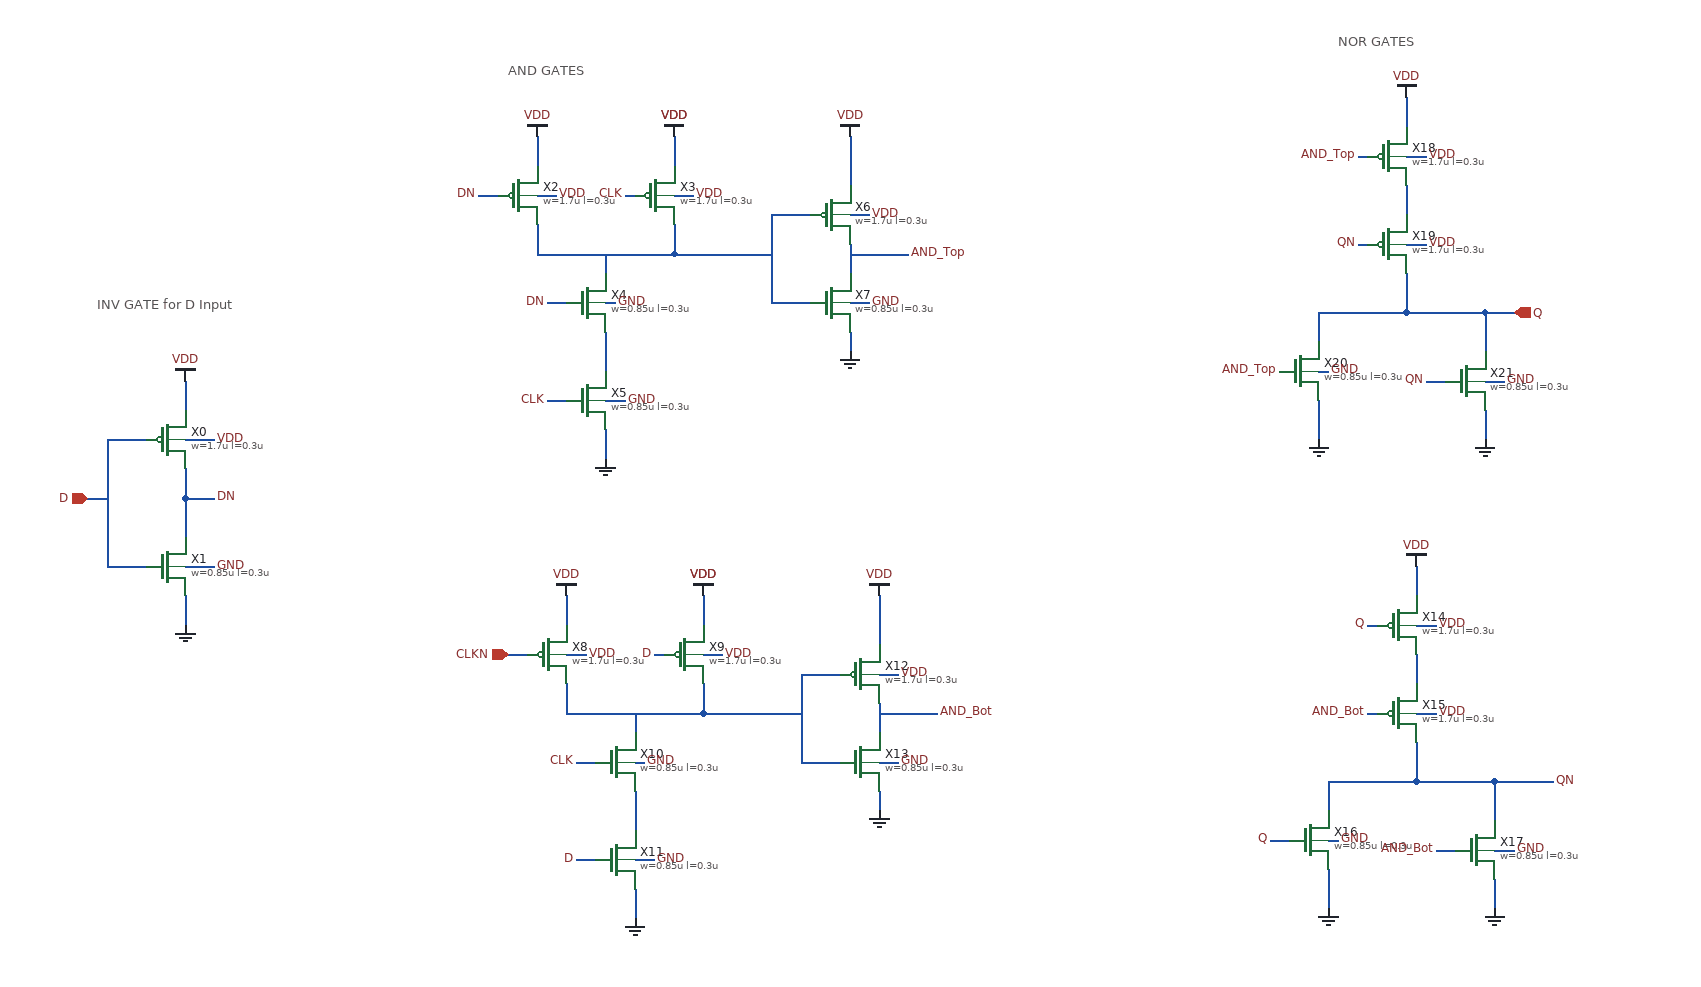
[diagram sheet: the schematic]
v {xschem version=3.0.0 file_version=1.2 }
G {}
K {}
V {}
S {}
E {}
T {AND GATES} 520 -910 0 0 0.4 0.4 {}
T {NOR GATES} 1370 -940 0 0 0.4 0.4 {}
T {INV GATE for D Input} 100 -670 0 0 0.4 0.4 {}
N 190 -580 190 -550 { lab=VDD}
N 190 -490 190 -460 { lab=DN}
N 190 -460 190 -420 { lab=DN}
N 190 -360 190 -330 { lab=GND}
N 130 -520 150 -520 { lab=D}
N 110 -520 110 -390 { lab=D}
N 90 -460 110 -460 { lab=D}
N 110 -520 130 -520 { lab=D}
N 110 -390 150 -390 { lab=D}
N 190 -520 220 -520 { lab=VDD}
N 190 -390 220 -390 { lab=GND}
N 190 -460 220 -460 { lab=DN}
N 550 -830 550 -800 { lab=VDD}
N 690 -830 690 -800 { lab=VDD}
N 550 -740 550 -710 { lab=#net1}
N 550 -710 690 -710 { lab=#net1}
N 690 -740 690 -710 { lab=#net1}
N 620 -710 620 -690 { lab=#net1}
N 620 -630 620 -590 { lab=#net2}
N 620 -530 620 -500 { lab=GND}
N 490 -770 510 -770 { lab=DN}
N 640 -770 650 -770 { lab=CLK}
N 870 -710 930 -710 { lab=AND_Top}
N 550 -770 570 -770 { lab=VDD}
N 690 -770 710 -770 { lab=VDD}
N 620 -660 630 -660 { lab=GND}
N 620 -560 640 -560 { lab=GND}
N 560 -660 580 -660 { lab=DN}
N 560 -560 580 -560 { lab=CLK}
N 870 -720 870 -690 { lab=AND_Top}
N 790 -660 830 -660 { lab=#net1}
N 790 -740 790 -660 { lab=#net1}
N 790 -750 790 -740 { lab=#net1}
N 790 -750 830 -750 { lab=#net1}
N 690 -710 790 -710 { lab=#net1}
N 870 -830 870 -780 { lab=VDD}
N 870 -630 870 -610 { lab=GND}
N 870 -750 890 -750 { lab=VDD}
N 870 -660 890 -660 { lab=GND}
N 580 -360 580 -330 { lab=VDD}
N 720 -360 720 -330 { lab=VDD}
N 580 -270 580 -240 { lab=#net3}
N 580 -240 720 -240 { lab=#net3}
N 720 -270 720 -240 { lab=#net3}
N 650 -240 650 -220 { lab=#net3}
N 650 -160 650 -120 { lab=#net4}
N 650 -60 650 -30 { lab=GND}
N 520 -300 540 -300 { lab=CLK}
N 670 -300 680 -300 { lab=D}
N 900 -240 960 -240 { lab=AND_Bot}
N 580 -300 600 -300 { lab=VDD}
N 720 -300 740 -300 { lab=VDD}
N 650 -190 660 -190 { lab=GND}
N 650 -90 670 -90 { lab=GND}
N 590 -190 610 -190 { lab=CLK}
N 590 -90 610 -90 { lab=D}
N 900 -250 900 -220 { lab=AND_Bot}
N 820 -190 860 -190 { lab=#net3}
N 820 -270 820 -190 { lab=#net3}
N 820 -280 820 -270 { lab=#net3}
N 820 -280 860 -280 { lab=#net3}
N 720 -240 820 -240 { lab=#net3}
N 900 -360 900 -310 { lab=VDD}
N 900 -160 900 -140 { lab=GND}
N 900 -280 920 -280 { lab=VDD}
N 900 -190 920 -190 { lab=GND}
N 1450 -390 1450 -360 { lab=VDD}
N 1450 -300 1450 -270 { lab=#net5}
N 1360 -80 1360 -40 { lab=GND}
N 1530 -70 1530 -40 { lab=GND}
N 1400 -240 1410 -240 { lab=AND_Bot}
N 1450 -330 1470 -330 { lab=VDD}
N 1450 -240 1470 -240 { lab=VDD}
N 1360 -110 1370 -110 { lab=GND}
N 1530 -100 1550 -100 { lab=GND}
N 1300 -110 1320 -110 { lab=Q}
N 1470 -100 1490 -100 { lab=AND_Bot}
N 1360 -170 1360 -140 { lab=QN}
N 1450 -210 1450 -170 { lab=QN}
N 1360 -170 1450 -170 { lab=QN}
N 1530 -170 1530 -130 { lab=QN}
N 1450 -170 1530 -170 { lab=QN}
N 1400 -330 1410 -330 { lab=Q}
N 1440 -870 1440 -840 { lab=VDD}
N 1440 -780 1440 -750 { lab=#net6}
N 1350 -560 1350 -520 { lab=GND}
N 1520 -550 1520 -520 { lab=GND}
N 1390 -720 1400 -720 { lab=QN}
N 1440 -810 1460 -810 { lab=VDD}
N 1440 -720 1460 -720 { lab=VDD}
N 1350 -590 1360 -590 { lab=GND}
N 1520 -580 1540 -580 { lab=GND}
N 1460 -580 1480 -580 { lab=QN}
N 1350 -650 1350 -620 { lab=Q}
N 1440 -690 1440 -650 { lab=Q}
N 1350 -650 1440 -650 { lab=Q}
N 1520 -650 1520 -610 { lab=Q}
N 1440 -650 1520 -650 { lab=Q}
N 1520 -650 1550 -650 { lab=Q}
N 1390 -810 1400 -810 { lab=AND_Top}
N 1530 -170 1590 -170 { lab=QN}
C {vdd.sym} 190 -580 0 0 {name=l1 lab=VDD}
C {gnd.sym} 190 -330 0 0 {name=l3 lab=GND}
C {ipin.sym} 90 -460 0 0 {name=p3 lab=D
}
C {pmos4.sym} 170 -520 0 0 {name=X0 model=pmos_3p3 w=1.7u l=0.3u m=1}
C {nmos4.sym} 170 -390 0 0 {name=X1 model=nmos_3p3 w=0.85u l=0.3u m=1}
C {lab_wire.sym} 220 -520 2 0 {name=l2 sig_type=std_logic lab=VDD
}
C {lab_wire.sym} 220 -390 2 0 {name=l4 sig_type=std_logic lab=GND
}
C {lab_wire.sym} 220 -460 2 0 {name=l5 sig_type=std_logic lab=DN}
C {vdd.sym} 550 -830 0 0 {name=l6 lab=VDD}
C {vdd.sym} 690 -830 0 0 {name=l7 lab=VDD}
C {gnd.sym} 620 -500 0 0 {name=l8 lab=GND}
C {pmos4.sym} 530 -770 0 0 {name=X2 model=pmos_3p3 w=1.7u l=0.3u m=1}
C {pmos4.sym} 670 -770 0 0 {name=X3 model=pmos_3p3 w=1.7u l=0.3u m=1}
C {nmos4.sym} 600 -660 0 0 {name=X4 model=nmos_3p3 w=0.85u l=0.3u m=1}
C {nmos4.sym} 600 -560 0 0 {name=X5 model=nmos_3p3 w=0.85u l=0.3u m=1}
C {lab_wire.sym} 570 -770 2 0 {name=l9 sig_type=std_logic lab=VDD}
C {lab_wire.sym} 710 -770 2 0 {name=l10 sig_type=std_logic lab=VDD}
C {lab_wire.sym} 630 -660 2 0 {name=l11 sig_type=std_logic lab=GND}
C {lab_wire.sym} 640 -560 2 0 {name=l12 sig_type=std_logic lab=GND}
C {lab_wire.sym} 560 -560 0 0 {name=l14 sig_type=std_logic lab=CLK}
C {pmos4.sym} 850 -750 0 0 {name=X6 model=pmos_3p3 w=1.7u l=0.3u m=1}
C {nmos4.sym} 850 -660 0 0 {name=X7 model=nmos_3p3 w=0.85u l=0.3u m=1}
C {vdd.sym} 690 -830 0 0 {name=l15 lab=VDD}
C {vdd.sym} 870 -830 0 0 {name=l16 lab=VDD}
C {gnd.sym} 870 -610 0 0 {name=l17 lab=GND}
C {lab_wire.sym} 890 -750 2 0 {name=l18 sig_type=std_logic lab=VDD}
C {lab_wire.sym} 890 -660 2 0 {name=l19 sig_type=std_logic lab=GND}
C {vdd.sym} 580 -360 0 0 {name=l20 lab=VDD}
C {vdd.sym} 720 -360 0 0 {name=l21 lab=VDD}
C {gnd.sym} 650 -30 0 0 {name=l22 lab=GND}
C {ipin.sym} 520 -300 0 0 {name=p2 lab=CLKN
}
C {pmos4.sym} 560 -300 0 0 {name=X8 model=pmos_3p3 w=1.7u l=0.3u m=1}
C {pmos4.sym} 700 -300 0 0 {name=X9 model=pmos_3p3 w=1.7u l=0.3u m=1}
C {nmos4.sym} 630 -190 0 0 {name=X10 model=nmos_3p3 w=0.85u l=0.3u m=1}
C {nmos4.sym} 630 -90 0 0 {name=X11 model=nmos_3p3 w=0.85u l=0.3u m=1}
C {lab_wire.sym} 600 -300 2 0 {name=l23 sig_type=std_logic lab=VDD}
C {lab_wire.sym} 740 -300 2 0 {name=l24 sig_type=std_logic lab=VDD}
C {lab_wire.sym} 660 -190 2 0 {name=l25 sig_type=std_logic lab=GND}
C {lab_wire.sym} 670 -90 2 0 {name=l26 sig_type=std_logic lab=GND}
C {lab_wire.sym} 590 -190 0 0 {name=l27 sig_type=std_logic lab=CLK}
C {lab_wire.sym} 590 -90 0 0 {name=l28 sig_type=std_logic lab=D}
C {pmos4.sym} 880 -280 0 0 {name=X12 model=pmos_3p3 w=1.7u l=0.3u m=1}
C {nmos4.sym} 880 -190 0 0 {name=X13 model=nmos_3p3 w=0.85u l=0.3u m=1}
C {vdd.sym} 720 -360 0 0 {name=l29 lab=VDD}
C {vdd.sym} 900 -360 0 0 {name=l30 lab=VDD}
C {gnd.sym} 900 -140 0 0 {name=l31 lab=GND}
C {lab_wire.sym} 920 -280 2 0 {name=l32 sig_type=std_logic lab=VDD}
C {lab_wire.sym} 920 -190 2 0 {name=l33 sig_type=std_logic lab=GND}
C {vdd.sym} 1450 -390 0 0 {name=l34 lab=VDD}
C {gnd.sym} 1360 -40 0 0 {name=l35 lab=GND}
C {pmos4.sym} 1430 -330 0 0 {name=X14 model=pmos_3p3 w=1.7u l=0.3u m=1}
C {pmos4.sym} 1430 -240 0 0 {name=X15 model=pmos_3p3 w=1.7u l=0.3u m=1}
C {nmos4.sym} 1340 -110 0 0 {name=X16 model=nmos_3p3 w=0.85u l=0.3u m=1}
C {nmos4.sym} 1510 -100 0 0 {name=X17 model=nmos_3p3 w=0.85u l=0.3u m=1}
C {lab_wire.sym} 1470 -330 2 0 {name=l36 sig_type=std_logic lab=VDD}
C {lab_wire.sym} 1470 -240 2 0 {name=l37 sig_type=std_logic lab=VDD}
C {lab_wire.sym} 1370 -110 2 0 {name=l38 sig_type=std_logic lab=GND}
C {lab_wire.sym} 1550 -100 2 0 {name=l39 sig_type=std_logic lab=GND}
C {gnd.sym} 1530 -40 0 0 {name=l42 lab=GND}
C {vdd.sym} 1440 -870 0 0 {name=l43 lab=VDD}
C {gnd.sym} 1350 -520 0 0 {name=l44 lab=GND}
C {opin.sym} 1550 -650 0 0 {name=p13 lab=Q}
C {pmos4.sym} 1420 -810 0 0 {name=X18 model=pmos_3p3 w=1.7u l=0.3u m=1}
C {pmos4.sym} 1420 -720 0 0 {name=X19 model=pmos_3p3 w=1.7u l=0.3u m=1}
C {nmos4.sym} 1330 -590 0 0 {name=X20 model=nmos_3p3 w=0.85u l=0.3u m=1}
C {nmos4.sym} 1500 -580 0 0 {name=X21 model=nmos_3p3 w=0.85u l=0.3u m=1}
C {lab_wire.sym} 1460 -810 2 0 {name=l45 sig_type=std_logic lab=VDD}
C {lab_wire.sym} 1460 -720 2 0 {name=l46 sig_type=std_logic lab=VDD}
C {lab_wire.sym} 1360 -590 2 0 {name=l47 sig_type=std_logic lab=GND}
C {lab_wire.sym} 1540 -580 2 0 {name=l48 sig_type=std_logic lab=GND}
C {gnd.sym} 1520 -520 0 0 {name=l51 lab=GND}
C {lab_wire.sym} 490 -770 0 0 {name=l52 sig_type=std_logic lab=DN}
C {lab_wire.sym} 560 -660 0 0 {name=l53 sig_type=std_logic lab=DN}
C {lab_wire.sym} 640 -770 0 0 {name=l13 sig_type=std_logic lab=CLK}
C {lab_wire.sym} 670 -300 0 0 {name=l54 sig_type=std_logic lab=D}
C {lab_wire.sym} 930 -710 2 0 {name=l49 sig_type=std_logic lab=AND_Top}
C {lab_wire.sym} 1390 -810 0 0 {name=l50 sig_type=std_logic lab=AND_Top}
C {lab_wire.sym} 1310 -590 0 0 {name=l55 sig_type=std_logic lab=AND_Top}
C {lab_wire.sym} 960 -240 2 0 {name=l56 sig_type=std_logic lab=AND_Bot}
C {lab_wire.sym} 1400 -240 0 0 {name=l57 sig_type=std_logic lab=AND_Bot}
C {lab_wire.sym} 1470 -100 0 0 {name=l41 sig_type=std_logic lab=AND_Bot}
C {lab_wire.sym} 1400 -330 0 0 {name=l40 sig_type=std_logic lab=Q}
C {lab_wire.sym} 1300 -110 0 0 {name=l58 sig_type=std_logic lab=Q}
C {lab_wire.sym} 1590 -170 2 0 {name=l59 sig_type=std_logic lab=QN}
C {lab_wire.sym} 1460 -580 0 0 {name=l60 sig_type=std_logic lab=QN}
C {lab_wire.sym} 1390 -720 0 0 {name=l61 sig_type=std_logic lab=QN}
